VERSION 5.8 ;
BUSBITCHARS "[]" ;
DIVIDERCHAR "/" ;
UNITS
    DATABASE MICRONS 2000 ;
END UNITS

VIA gemm_mac_fp16_ieee_via1_2_960_340_1_3_300_300
  VIARULE Via1Array-0 ;
  CUTSIZE 0.07 0.07 ;
  LAYERS metal1 via1 metal2 ;
  CUTSPACING 0.08 0.08 ;
  ENCLOSURE 0.035 0.05 0.035 0.035 ;
  ROWCOL 1 3 ;
END gemm_mac_fp16_ieee_via1_2_960_340_1_3_300_300

VIA gemm_mac_fp16_ieee_via2_3_960_340_1_3_320_320
  VIARULE Via2Array-0 ;
  CUTSIZE 0.07 0.07 ;
  LAYERS metal2 via2 metal3 ;
  CUTSPACING 0.09 0.09 ;
  ENCLOSURE 0.035 0.035 0.035 0.035 ;
  ROWCOL 1 3 ;
END gemm_mac_fp16_ieee_via2_3_960_340_1_3_320_320

VIA gemm_mac_fp16_ieee_via3_4_960_340_1_3_320_320
  VIARULE Via3Array-0 ;
  CUTSIZE 0.07 0.07 ;
  LAYERS metal3 via3 metal4 ;
  CUTSPACING 0.09 0.09 ;
  ENCLOSURE 0.035 0.035 0.045 0.035 ;
  ROWCOL 1 3 ;
END gemm_mac_fp16_ieee_via3_4_960_340_1_3_320_320

VIA gemm_mac_fp16_ieee_via4_5_960_2800_5_2_600_600
  VIARULE Via4Array-0 ;
  CUTSIZE 0.14 0.14 ;
  LAYERS metal4 via4 metal5 ;
  CUTSPACING 0.16 0.16 ;
  ENCLOSURE 0.02 0 0 0 ;
  ROWCOL 5 2 ;
END gemm_mac_fp16_ieee_via4_5_960_2800_5_2_600_600

VIA gemm_mac_fp16_ieee_via5_6_960_2800_5_2_600_600
  VIARULE Via5Array-0 ;
  CUTSIZE 0.14 0.14 ;
  LAYERS metal5 via5 metal6 ;
  CUTSPACING 0.16 0.16 ;
  ENCLOSURE 0 0 0 0 ;
  ROWCOL 5 2 ;
END gemm_mac_fp16_ieee_via5_6_960_2800_5_2_600_600

VIA gemm_mac_fp16_ieee_via6_7_960_2800_4_1_600_600
  VIARULE Via6Array-0 ;
  CUTSIZE 0.14 0.14 ;
  LAYERS metal6 via6 metal7 ;
  CUTSPACING 0.16 0.16 ;
  ENCLOSURE 0 0 0.13 0.18 ;
  ROWCOL 4 1 ;
END gemm_mac_fp16_ieee_via6_7_960_2800_4_1_600_600

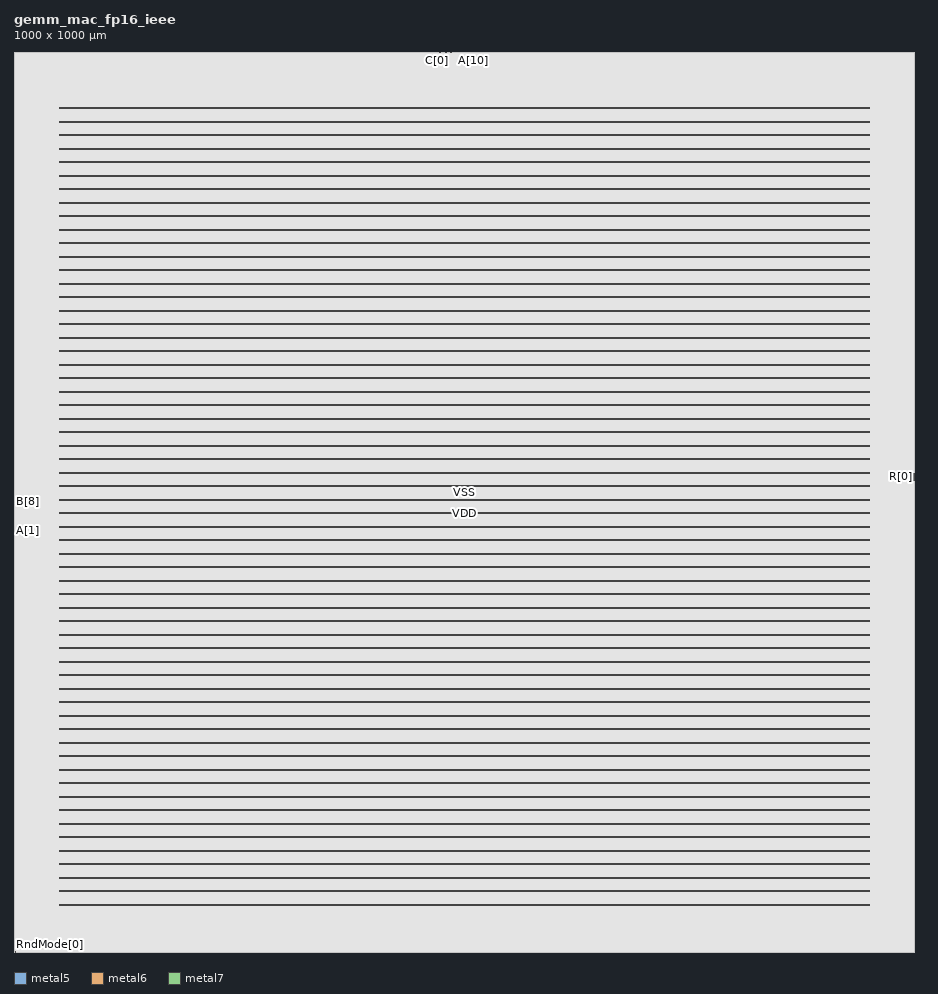
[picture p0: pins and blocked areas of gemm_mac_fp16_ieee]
MACRO gemm_mac_fp16_ieee
  FOREIGN gemm_mac_fp16_ieee 0 0 ;
  CLASS BLOCK ;
  SIZE 1000 BY 1000 ;
  PIN A[0]
    DIRECTION INPUT ;
    USE SIGNAL ;
    PORT
      LAYER metal5 ;
        RECT  0 470.4 0.14 470.54 ;
    END
  END A[0]
  PIN A[10]
    DIRECTION INPUT ;
    USE SIGNAL ;
    PORT
      LAYER metal6 ;
        RECT  510.185 999.86 510.325 1000 ;
    END
  END A[10]
  PIN A[11]
    DIRECTION INPUT ;
    USE SIGNAL ;
    PORT
      LAYER metal6 ;
        RECT  515.225 999.86 515.365 1000 ;
    END
  END A[11]
  PIN A[12]
    DIRECTION INPUT ;
    USE SIGNAL ;
    PORT
      LAYER metal6 ;
        RECT  512.425 999.86 512.565 1000 ;
    END
  END A[12]
  PIN A[13]
    DIRECTION INPUT ;
    USE SIGNAL ;
    PORT
      LAYER metal6 ;
        RECT  514.105 999.86 514.245 1000 ;
    END
  END A[13]
  PIN A[14]
    DIRECTION INPUT ;
    USE SIGNAL ;
    PORT
      LAYER metal6 ;
        RECT  505.705 999.86 505.845 1000 ;
    END
  END A[14]
  PIN A[15]
    DIRECTION INPUT ;
    USE SIGNAL ;
    PORT
      LAYER metal6 ;
        RECT  500.105 999.86 500.245 1000 ;
    END
  END A[15]
  PIN A[1]
    DIRECTION INPUT ;
    USE SIGNAL ;
    PORT
      LAYER metal5 ;
        RECT  0 468.16 0.14 468.3 ;
    END
  END A[1]
  PIN A[2]
    DIRECTION INPUT ;
    USE SIGNAL ;
    PORT
      LAYER metal5 ;
        RECT  0 467.6 0.14 467.74 ;
    END
  END A[2]
  PIN A[3]
    DIRECTION INPUT ;
    USE SIGNAL ;
    PORT
      LAYER metal5 ;
        RECT  0 467.04 0.14 467.18 ;
    END
  END A[3]
  PIN A[4]
    DIRECTION INPUT ;
    USE SIGNAL ;
    PORT
      LAYER metal5 ;
        RECT  0 463.68 0.14 463.82 ;
    END
  END A[4]
  PIN A[5]
    DIRECTION INPUT ;
    USE SIGNAL ;
    PORT
      LAYER metal5 ;
        RECT  0 462.56 0.14 462.7 ;
    END
  END A[5]
  PIN A[6]
    DIRECTION INPUT ;
    USE SIGNAL ;
    PORT
      LAYER metal5 ;
        RECT  0 462 0.14 462.14 ;
    END
  END A[6]
  PIN A[7]
    DIRECTION INPUT ;
    USE SIGNAL ;
    PORT
      LAYER metal5 ;
        RECT  0 465.92 0.14 466.06 ;
    END
  END A[7]
  PIN A[8]
    DIRECTION INPUT ;
    USE SIGNAL ;
    PORT
      LAYER metal5 ;
        RECT  0 471.52 0.14 471.66 ;
    END
  END A[8]
  PIN A[9]
    DIRECTION INPUT ;
    USE SIGNAL ;
    PORT
      LAYER metal5 ;
        RECT  0 466.48 0.14 466.62 ;
    END
  END A[9]
  PIN B[0]
    DIRECTION INPUT ;
    USE SIGNAL ;
    PORT
      LAYER metal5 ;
        RECT  0 469.84 0.14 469.98 ;
    END
  END B[0]
  PIN B[10]
    DIRECTION INPUT ;
    USE SIGNAL ;
    PORT
      LAYER metal6 ;
        RECT  509.065 999.86 509.205 1000 ;
    END
  END B[10]
  PIN B[11]
    DIRECTION INPUT ;
    USE SIGNAL ;
    PORT
      LAYER metal6 ;
        RECT  515.785 999.86 515.925 1000 ;
    END
  END B[11]
  PIN B[12]
    DIRECTION INPUT ;
    USE SIGNAL ;
    PORT
      LAYER metal6 ;
        RECT  511.865 999.86 512.005 1000 ;
    END
  END B[12]
  PIN B[13]
    DIRECTION INPUT ;
    USE SIGNAL ;
    PORT
      LAYER metal6 ;
        RECT  514.665 999.86 514.805 1000 ;
    END
  END B[13]
  PIN B[14]
    DIRECTION INPUT ;
    USE SIGNAL ;
    PORT
      LAYER metal6 ;
        RECT  508.505 999.86 508.645 1000 ;
    END
  END B[14]
  PIN B[15]
    DIRECTION INPUT ;
    USE SIGNAL ;
    PORT
      LAYER metal6 ;
        RECT  499.545 999.86 499.685 1000 ;
    END
  END B[15]
  PIN B[1]
    DIRECTION INPUT ;
    USE SIGNAL ;
    PORT
      LAYER metal5 ;
        RECT  0 468.72 0.14 468.86 ;
    END
  END B[1]
  PIN B[2]
    DIRECTION INPUT ;
    USE SIGNAL ;
    PORT
      LAYER metal5 ;
        RECT  0 469.28 0.14 469.42 ;
    END
  END B[2]
  PIN B[3]
    DIRECTION INPUT ;
    USE SIGNAL ;
    PORT
      LAYER metal5 ;
        RECT  0 470.96 0.14 471.1 ;
    END
  END B[3]
  PIN B[4]
    DIRECTION INPUT ;
    USE SIGNAL ;
    PORT
      LAYER metal5 ;
        RECT  0 464.24 0.14 464.38 ;
    END
  END B[4]
  PIN B[5]
    DIRECTION INPUT ;
    USE SIGNAL ;
    PORT
      LAYER metal5 ;
        RECT  0 463.12 0.14 463.26 ;
    END
  END B[5]
  PIN B[6]
    DIRECTION INPUT ;
    USE SIGNAL ;
    PORT
      LAYER metal5 ;
        RECT  0 464.8 0.14 464.94 ;
    END
  END B[6]
  PIN B[7]
    DIRECTION INPUT ;
    USE SIGNAL ;
    PORT
      LAYER metal5 ;
        RECT  0 465.36 0.14 465.5 ;
    END
  END B[7]
  PIN B[8]
    DIRECTION INPUT ;
    USE SIGNAL ;
    PORT
      LAYER metal5 ;
        RECT  0 500.64 0.14 500.78 ;
    END
  END B[8]
  PIN B[9]
    DIRECTION INPUT ;
    USE SIGNAL ;
    PORT
      LAYER metal5 ;
        RECT  0 472.64 0.14 472.78 ;
    END
  END B[9]
  PIN C[0]
    DIRECTION INPUT ;
    USE SIGNAL ;
    PORT
      LAYER metal6 ;
        RECT  470.425 999.86 470.565 1000 ;
    END
  END C[0]
  PIN C[10]
    DIRECTION INPUT ;
    USE SIGNAL ;
    PORT
      LAYER metal6 ;
        RECT  520.265 999.86 520.405 1000 ;
    END
  END C[10]
  PIN C[11]
    DIRECTION INPUT ;
    USE SIGNAL ;
    PORT
      LAYER metal6 ;
        RECT  524.185 999.86 524.325 1000 ;
    END
  END C[11]
  PIN C[12]
    DIRECTION INPUT ;
    USE SIGNAL ;
    PORT
      LAYER metal6 ;
        RECT  518.585 999.86 518.725 1000 ;
    END
  END C[12]
  PIN C[13]
    DIRECTION INPUT ;
    USE SIGNAL ;
    PORT
      LAYER metal6 ;
        RECT  518.025 999.86 518.165 1000 ;
    END
  END C[13]
  PIN C[14]
    DIRECTION INPUT ;
    USE SIGNAL ;
    PORT
      LAYER metal6 ;
        RECT  521.945 999.86 522.085 1000 ;
    END
  END C[14]
  PIN C[15]
    DIRECTION INPUT ;
    USE SIGNAL ;
    PORT
      LAYER metal6 ;
        RECT  500.665 999.86 500.805 1000 ;
    END
  END C[15]
  PIN C[1]
    DIRECTION INPUT ;
    USE SIGNAL ;
    PORT
      LAYER metal6 ;
        RECT  473.225 999.86 473.365 1000 ;
    END
  END C[1]
  PIN C[2]
    DIRECTION INPUT ;
    USE SIGNAL ;
    PORT
      LAYER metal6 ;
        RECT  473.785 999.86 473.925 1000 ;
    END
  END C[2]
  PIN C[3]
    DIRECTION INPUT ;
    USE SIGNAL ;
    PORT
      LAYER metal6 ;
        RECT  472.665 999.86 472.805 1000 ;
    END
  END C[3]
  PIN C[4]
    DIRECTION INPUT ;
    USE SIGNAL ;
    PORT
      LAYER metal6 ;
        RECT  480.505 999.86 480.645 1000 ;
    END
  END C[4]
  PIN C[5]
    DIRECTION INPUT ;
    USE SIGNAL ;
    PORT
      LAYER metal6 ;
        RECT  479.945 999.86 480.085 1000 ;
    END
  END C[5]
  PIN C[6]
    DIRECTION INPUT ;
    USE SIGNAL ;
    PORT
      LAYER metal6 ;
        RECT  479.385 999.86 479.525 1000 ;
    END
  END C[6]
  PIN C[7]
    DIRECTION INPUT ;
    USE SIGNAL ;
    PORT
      LAYER metal6 ;
        RECT  481.625 999.86 481.765 1000 ;
    END
  END C[7]
  PIN C[8]
    DIRECTION INPUT ;
    USE SIGNAL ;
    PORT
      LAYER metal6 ;
        RECT  485.545 999.86 485.685 1000 ;
    END
  END C[8]
  PIN C[9]
    DIRECTION INPUT ;
    USE SIGNAL ;
    PORT
      LAYER metal6 ;
        RECT  491.705 999.86 491.845 1000 ;
    END
  END C[9]
  PIN R[0]
    DIRECTION OUTPUT ;
    USE SIGNAL ;
    PORT
      LAYER metal5 ;
        RECT  999.86 528.64 1000 528.78 ;
    END
  END R[0]
  PIN R[10]
    DIRECTION OUTPUT ;
    USE SIGNAL ;
    PORT
      LAYER metal5 ;
        RECT  999.86 526.4 1000 526.54 ;
    END
  END R[10]
  PIN R[11]
    DIRECTION OUTPUT ;
    USE SIGNAL ;
    PORT
      LAYER metal5 ;
        RECT  999.86 527.52 1000 527.66 ;
    END
  END R[11]
  PIN R[12]
    DIRECTION OUTPUT ;
    USE SIGNAL ;
    PORT
      LAYER metal5 ;
        RECT  999.86 526.96 1000 527.1 ;
    END
  END R[12]
  PIN R[13]
    DIRECTION OUTPUT ;
    USE SIGNAL ;
    PORT
      LAYER metal5 ;
        RECT  999.86 531.44 1000 531.58 ;
    END
  END R[13]
  PIN R[14]
    DIRECTION OUTPUT ;
    USE SIGNAL ;
    PORT
      LAYER metal5 ;
        RECT  999.86 530.88 1000 531.02 ;
    END
  END R[14]
  PIN R[15]
    DIRECTION OUTPUT ;
    USE SIGNAL ;
    PORT
      LAYER metal6 ;
        RECT  506.265 999.86 506.405 1000 ;
    END
  END R[15]
  PIN R[1]
    DIRECTION OUTPUT ;
    USE SIGNAL ;
    PORT
      LAYER metal5 ;
        RECT  999.86 529.76 1000 529.9 ;
    END
  END R[1]
  PIN R[2]
    DIRECTION OUTPUT ;
    USE SIGNAL ;
    PORT
      LAYER metal5 ;
        RECT  999.86 523.6 1000 523.74 ;
    END
  END R[2]
  PIN R[3]
    DIRECTION OUTPUT ;
    USE SIGNAL ;
    PORT
      LAYER metal5 ;
        RECT  999.86 529.2 1000 529.34 ;
    END
  END R[3]
  PIN R[4]
    DIRECTION OUTPUT ;
    USE SIGNAL ;
    PORT
      LAYER metal5 ;
        RECT  999.86 524.16 1000 524.3 ;
    END
  END R[4]
  PIN R[5]
    DIRECTION OUTPUT ;
    USE SIGNAL ;
    PORT
      LAYER metal5 ;
        RECT  999.86 525.84 1000 525.98 ;
    END
  END R[5]
  PIN R[6]
    DIRECTION OUTPUT ;
    USE SIGNAL ;
    PORT
      LAYER metal5 ;
        RECT  999.86 530.32 1000 530.46 ;
    END
  END R[6]
  PIN R[7]
    DIRECTION OUTPUT ;
    USE SIGNAL ;
    PORT
      LAYER metal5 ;
        RECT  999.86 525.28 1000 525.42 ;
    END
  END R[7]
  PIN R[8]
    DIRECTION OUTPUT ;
    USE SIGNAL ;
    PORT
      LAYER metal5 ;
        RECT  999.86 528.08 1000 528.22 ;
    END
  END R[8]
  PIN R[9]
    DIRECTION OUTPUT ;
    USE SIGNAL ;
    PORT
      LAYER metal5 ;
        RECT  999.86 524.72 1000 524.86 ;
    END
  END R[9]
  PIN RndMode[0]
    DIRECTION INPUT ;
    USE SIGNAL ;
    PORT
      LAYER metal6 ;
        RECT  1.145 0 1.285 0.14 ;
    END
  END RndMode[0]
  PIN RndMode[1]
    DIRECTION INPUT ;
    USE SIGNAL ;
    PORT
      LAYER metal6 ;
        RECT  1.705 0 1.845 0.14 ;
    END
  END RndMode[1]
  PIN negateAB
    DIRECTION INPUT ;
    USE SIGNAL ;
    PORT
      LAYER metal6 ;
        RECT  501.225 999.86 501.365 1000 ;
    END
  END negateAB
  PIN negateC
    DIRECTION INPUT ;
    USE SIGNAL ;
    PORT
      LAYER metal6 ;
        RECT  501.785 999.86 501.925 1000 ;
    END
  END negateC
  PIN VSS
    DIRECTION INOUT ;
    USE GROUND ;
    PORT
      LAYER metal7 ;
        RECT  50.16 921.7 950 923.1 ;
        RECT  50.16 891.7 950 893.1 ;
        RECT  50.16 861.7 950 863.1 ;
        RECT  50.16 831.7 950 833.1 ;
        RECT  50.16 801.7 950 803.1 ;
        RECT  50.16 771.7 950 773.1 ;
        RECT  50.16 741.7 950 743.1 ;
        RECT  50.16 711.7 950 713.1 ;
        RECT  50.16 681.7 950 683.1 ;
        RECT  50.16 651.7 950 653.1 ;
        RECT  50.16 621.7 950 623.1 ;
        RECT  50.16 591.7 950 593.1 ;
        RECT  50.16 561.7 950 563.1 ;
        RECT  50.16 531.7 950 533.1 ;
        RECT  50.16 501.7 950 503.1 ;
        RECT  50.16 471.7 950 473.1 ;
        RECT  50.16 441.7 950 443.1 ;
        RECT  50.16 411.7 950 413.1 ;
        RECT  50.16 381.7 950 383.1 ;
        RECT  50.16 351.7 950 353.1 ;
        RECT  50.16 321.7 950 323.1 ;
        RECT  50.16 291.7 950 293.1 ;
        RECT  50.16 261.7 950 263.1 ;
        RECT  50.16 231.7 950 233.1 ;
        RECT  50.16 201.7 950 203.1 ;
        RECT  50.16 171.7 950 173.1 ;
        RECT  50.16 141.7 950 143.1 ;
        RECT  50.16 111.7 950 113.1 ;
        RECT  50.16 81.7 950 83.1 ;
        RECT  50.16 51.7 950 53.1 ;
    END
  END VSS
  PIN VDD
    DIRECTION INOUT ;
    USE POWER ;
    PORT
      LAYER metal7 ;
        RECT  50.16 936.7 950 938.1 ;
        RECT  50.16 906.7 950 908.1 ;
        RECT  50.16 876.7 950 878.1 ;
        RECT  50.16 846.7 950 848.1 ;
        RECT  50.16 816.7 950 818.1 ;
        RECT  50.16 786.7 950 788.1 ;
        RECT  50.16 756.7 950 758.1 ;
        RECT  50.16 726.7 950 728.1 ;
        RECT  50.16 696.7 950 698.1 ;
        RECT  50.16 666.7 950 668.1 ;
        RECT  50.16 636.7 950 638.1 ;
        RECT  50.16 606.7 950 608.1 ;
        RECT  50.16 576.7 950 578.1 ;
        RECT  50.16 546.7 950 548.1 ;
        RECT  50.16 516.7 950 518.1 ;
        RECT  50.16 486.7 950 488.1 ;
        RECT  50.16 456.7 950 458.1 ;
        RECT  50.16 426.7 950 428.1 ;
        RECT  50.16 396.7 950 398.1 ;
        RECT  50.16 366.7 950 368.1 ;
        RECT  50.16 336.7 950 338.1 ;
        RECT  50.16 306.7 950 308.1 ;
        RECT  50.16 276.7 950 278.1 ;
        RECT  50.16 246.7 950 248.1 ;
        RECT  50.16 216.7 950 218.1 ;
        RECT  50.16 186.7 950 188.1 ;
        RECT  50.16 156.7 950 158.1 ;
        RECT  50.16 126.7 950 128.1 ;
        RECT  50.16 96.7 950 98.1 ;
        RECT  50.16 66.7 950 68.1 ;
    END
  END VDD
  OBS
    LAYER metal1 ;
     RECT  0 0 1000 1000 ;
    LAYER metal2 ;
     RECT  0 0 1000 1000 ;
    LAYER metal3 ;
     RECT  0 0 1000 1000 ;
    LAYER metal4 ;
     RECT  0 0 1000 1000 ;
    LAYER metal5 ;
     RECT  0 0 1000 1000 ;
    LAYER metal6 ;
     RECT  0 0 1000 1000 ;
    LAYER metal7 ;
     RECT  0 0 1000 1000 ;
    LAYER metal8 ;
     RECT  0 0 1000 1000 ;
  END
END gemm_mac_fp16_ieee
END LIBRARY
